###############################################################
#  Generated by:      Cadence Innovus 25.11-s102_1
#  OS:                Linux x86_64(Host ID ece-rhelsrv)
#  Generated on:      Sun Oct 11 20:42:43 2026
#  Design:            chip_top
#  Command:           write_lef_abstract /nethome/sgupta943/physical-design-onboarding-F26/outputs/apr/DBS/chip_top.lef -specifyTopLayer 5 -stripePin -extractBlockPGPinLayers 5
###############################################################

VERSION 5.8 ;

BUSBITCHARS "[]" ;
DIVIDERCHAR "/" ;

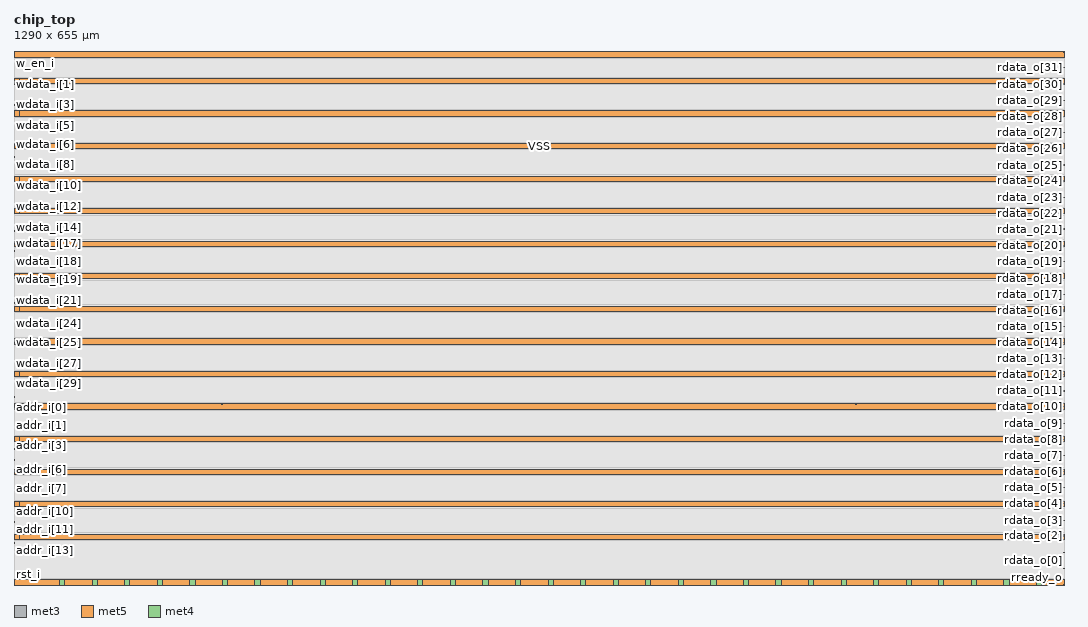
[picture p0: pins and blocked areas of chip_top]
MACRO chip_top
  CLASS BLOCK ;
  SIZE 1290.000000 BY 655.000000 ;
  FOREIGN chip_top 0.000000 0.000000 ;
  ORIGIN 0 0 ;
  SYMMETRY X Y R90 ;
  PIN clk_i
    DIRECTION INPUT ;
    USE SIGNAL ;
    PORT
      LAYER met3 ;
        RECT 0.000000 0.360000 0.800000 0.660000 ;
    END
  END clk_i
  PIN rst_i
    DIRECTION INPUT ;
    USE SIGNAL ;
    PORT
      LAYER met3 ;
        RECT 0.000000 12.560000 0.800000 12.860000 ;
    END
  END rst_i
  PIN en_cpu_i
    DIRECTION INPUT ;
    USE SIGNAL ;
    PORT
      LAYER met3 ;
        RECT 0.000000 25.980000 0.800000 26.280000 ;
    END
  END en_cpu_i
  PIN halt_cpu_i
    DIRECTION INPUT ;
    USE SIGNAL ;
    PORT
      LAYER met3 ;
        RECT 0.000000 39.400000 0.800000 39.700000 ;
    END
  END halt_cpu_i
  PIN cpu_halted_o
    DIRECTION OUTPUT ;
    USE SIGNAL ;
    PORT
      LAYER met3 ;
        RECT 1289.200000 654.280000 1290.000000 654.580000 ;
    END
  END cpu_halted_o
  PIN addr_i[13]
    DIRECTION INPUT ;
    USE SIGNAL ;
    PORT
      LAYER met3 ;
        RECT 0.000000 51.600000 0.800000 51.900000 ;
    END
  END addr_i[13]
  PIN addr_i[12]
    DIRECTION INPUT ;
    USE SIGNAL ;
    PORT
      LAYER met3 ;
        RECT 0.000000 64.410000 0.800000 64.710000 ;
    END
  END addr_i[12]
  PIN addr_i[11]
    DIRECTION INPUT ;
    USE SIGNAL ;
    PORT
      LAYER met3 ;
        RECT 0.000000 77.220000 0.800000 77.520000 ;
    END
  END addr_i[11]
  PIN addr_i[10]
    DIRECTION INPUT ;
    USE SIGNAL ;
    PORT
      LAYER met3 ;
        RECT 0.000000 90.030000 0.800000 90.330000 ;
    END
  END addr_i[10]
  PIN addr_i[9]
    DIRECTION INPUT ;
    USE SIGNAL ;
    PORT
      LAYER met3 ;
        RECT 0.000000 102.840000 0.800000 103.140000 ;
    END
  END addr_i[9]
  PIN addr_i[8]
    DIRECTION INPUT ;
    USE SIGNAL ;
    PORT
      LAYER met3 ;
        RECT 0.000000 115.650000 0.800000 115.950000 ;
    END
  END addr_i[8]
  PIN addr_i[7]
    DIRECTION INPUT ;
    USE SIGNAL ;
    PORT
      LAYER met3 ;
        RECT 0.000000 128.460000 0.800000 128.760000 ;
    END
  END addr_i[7]
  PIN addr_i[6]
    DIRECTION INPUT ;
    USE SIGNAL ;
    PORT
      LAYER met3 ;
        RECT 0.000000 141.270000 0.800000 141.570000 ;
    END
  END addr_i[6]
  PIN addr_i[5]
    DIRECTION INPUT ;
    USE SIGNAL ;
    PORT
      LAYER met3 ;
        RECT 0.000000 153.470000 0.800000 153.770000 ;
    END
  END addr_i[5]
  PIN addr_i[4]
    DIRECTION INPUT ;
    USE SIGNAL ;
    PORT
      LAYER met3 ;
        RECT 0.000000 166.890000 0.800000 167.190000 ;
    END
  END addr_i[4]
  PIN addr_i[3]
    DIRECTION INPUT ;
    USE SIGNAL ;
    PORT
      LAYER met3 ;
        RECT 0.000000 180.310000 0.800000 180.610000 ;
    END
  END addr_i[3]
  PIN addr_i[2]
    DIRECTION INPUT ;
    USE SIGNAL ;
    PORT
      LAYER met3 ;
        RECT 0.000000 192.510000 0.800000 192.810000 ;
    END
  END addr_i[2]
  PIN addr_i[1]
    DIRECTION INPUT ;
    USE SIGNAL ;
    PORT
      LAYER met3 ;
        RECT 0.000000 205.320000 0.800000 205.620000 ;
    END
  END addr_i[1]
  PIN addr_i[0]
    DIRECTION INPUT ;
    USE SIGNAL ;
    PORT
      LAYER met3 ;
        RECT 0.000000 218.130000 0.800000 218.430000 ;
    END
  END addr_i[0]
  PIN wdata_i[31]
    DIRECTION INPUT ;
    USE SIGNAL ;
    PORT
      LAYER met3 ;
        RECT 0.000000 230.940000 0.800000 231.240000 ;
    END
  END wdata_i[31]
  PIN wdata_i[30]
    DIRECTION INPUT ;
    USE SIGNAL ;
    PORT
      LAYER met3 ;
        RECT 0.000000 243.750000 0.800000 244.050000 ;
    END
  END wdata_i[30]
  PIN wdata_i[29]
    DIRECTION INPUT ;
    USE SIGNAL ;
    PORT
      LAYER met3 ;
        RECT 0.000000 256.560000 0.800000 256.860000 ;
    END
  END wdata_i[29]
  PIN wdata_i[28]
    DIRECTION INPUT ;
    USE SIGNAL ;
    PORT
      LAYER met3 ;
        RECT 0.000000 269.370000 0.800000 269.670000 ;
    END
  END wdata_i[28]
  PIN wdata_i[27]
    DIRECTION INPUT ;
    USE SIGNAL ;
    PORT
      LAYER met3 ;
        RECT 0.000000 282.180000 0.800000 282.480000 ;
    END
  END wdata_i[27]
  PIN wdata_i[26]
    DIRECTION INPUT ;
    USE SIGNAL ;
    PORT
      LAYER met3 ;
        RECT 0.000000 294.380000 0.800000 294.680000 ;
    END
  END wdata_i[26]
  PIN wdata_i[25]
    DIRECTION INPUT ;
    USE SIGNAL ;
    PORT
      LAYER met3 ;
        RECT 0.000000 307.800000 0.800000 308.100000 ;
    END
  END wdata_i[25]
  PIN wdata_i[24]
    DIRECTION INPUT ;
    USE SIGNAL ;
    PORT
      LAYER met3 ;
        RECT 0.000000 321.220000 0.800000 321.520000 ;
    END
  END wdata_i[24]
  PIN wdata_i[23]
    DIRECTION INPUT ;
    USE SIGNAL ;
    PORT
      LAYER met3 ;
        RECT 0.000000 333.420000 0.800000 333.720000 ;
    END
  END wdata_i[23]
  PIN wdata_i[22]
    DIRECTION INPUT ;
    USE SIGNAL ;
    PORT
      LAYER met3 ;
        RECT 0.000000 346.230000 0.800000 346.530000 ;
    END
  END wdata_i[22]
  PIN wdata_i[21]
    DIRECTION INPUT ;
    USE SIGNAL ;
    PORT
      LAYER met3 ;
        RECT 0.000000 359.040000 0.800000 359.340000 ;
    END
  END wdata_i[21]
  PIN wdata_i[20]
    DIRECTION INPUT ;
    USE SIGNAL ;
    PORT
      LAYER met3 ;
        RECT 0.000000 371.850000 0.800000 372.150000 ;
    END
  END wdata_i[20]
  PIN wdata_i[19]
    DIRECTION INPUT ;
    USE SIGNAL ;
    PORT
      LAYER met3 ;
        RECT 0.000000 384.660000 0.800000 384.960000 ;
    END
  END wdata_i[19]
  PIN wdata_i[18]
    DIRECTION INPUT ;
    USE SIGNAL ;
    PORT
      LAYER met3 ;
        RECT 0.000000 397.470000 0.800000 397.770000 ;
    END
  END wdata_i[18]
  PIN wdata_i[17]
    DIRECTION INPUT ;
    USE SIGNAL ;
    PORT
      LAYER met3 ;
        RECT 0.000000 410.280000 0.800000 410.580000 ;
    END
  END wdata_i[17]
  PIN wdata_i[16]
    DIRECTION INPUT ;
    USE SIGNAL ;
    PORT
      LAYER met3 ;
        RECT 0.000000 423.090000 0.800000 423.390000 ;
    END
  END wdata_i[16]
  PIN wdata_i[15]
    DIRECTION INPUT ;
    USE SIGNAL ;
    PORT
      LAYER met3 ;
        RECT 0.000000 434.680000 0.800000 434.980000 ;
    END
  END wdata_i[15]
  PIN wdata_i[14]
    DIRECTION INPUT ;
    USE SIGNAL ;
    PORT
      LAYER met3 ;
        RECT 0.000000 448.710000 0.800000 449.010000 ;
    END
  END wdata_i[14]
  PIN wdata_i[13]
    DIRECTION INPUT ;
    USE SIGNAL ;
    PORT
      LAYER met3 ;
        RECT 0.000000 461.520000 0.800000 461.820000 ;
    END
  END wdata_i[13]
  PIN wdata_i[12]
    DIRECTION INPUT ;
    USE SIGNAL ;
    PORT
      LAYER met3 ;
        RECT 0.000000 474.330000 0.800000 474.630000 ;
    END
  END wdata_i[12]
  PIN wdata_i[11]
    DIRECTION INPUT ;
    USE SIGNAL ;
    PORT
      LAYER met3 ;
        RECT 0.000000 487.140000 0.800000 487.440000 ;
    END
  END wdata_i[11]
  PIN wdata_i[10]
    DIRECTION INPUT ;
    USE SIGNAL ;
    PORT
      LAYER met3 ;
        RECT 0.000000 499.950000 0.800000 500.250000 ;
    END
  END wdata_i[10]
  PIN wdata_i[9]
    DIRECTION INPUT ;
    USE SIGNAL ;
    PORT
      LAYER met3 ;
        RECT 0.000000 512.760000 0.800000 513.060000 ;
    END
  END wdata_i[9]
  PIN wdata_i[8]
    DIRECTION INPUT ;
    USE SIGNAL ;
    PORT
      LAYER met3 ;
        RECT 0.000000 525.570000 0.800000 525.870000 ;
    END
  END wdata_i[8]
  PIN wdata_i[7]
    DIRECTION INPUT ;
    USE SIGNAL ;
    PORT
      LAYER met3 ;
        RECT 0.000000 538.380000 0.800000 538.680000 ;
    END
  END wdata_i[7]
  PIN wdata_i[6]
    DIRECTION INPUT ;
    USE SIGNAL ;
    PORT
      LAYER met3 ;
        RECT 0.000000 551.190000 0.800000 551.490000 ;
    END
  END wdata_i[6]
  PIN wdata_i[5]
    DIRECTION INPUT ;
    USE SIGNAL ;
    PORT
      LAYER met3 ;
        RECT 0.000000 564.000000 0.800000 564.300000 ;
    END
  END wdata_i[5]
  PIN wdata_i[4]
    DIRECTION INPUT ;
    USE SIGNAL ;
    PORT
      LAYER met3 ;
        RECT 0.000000 577.420000 0.800000 577.720000 ;
    END
  END wdata_i[4]
  PIN wdata_i[3]
    DIRECTION INPUT ;
    USE SIGNAL ;
    PORT
      LAYER met3 ;
        RECT 0.000000 589.620000 0.800000 589.920000 ;
    END
  END wdata_i[3]
  PIN wdata_i[2]
    DIRECTION INPUT ;
    USE SIGNAL ;
    PORT
      LAYER met3 ;
        RECT 0.000000 602.430000 0.800000 602.730000 ;
    END
  END wdata_i[2]
  PIN wdata_i[1]
    DIRECTION INPUT ;
    USE SIGNAL ;
    PORT
      LAYER met3 ;
        RECT 0.000000 615.240000 0.800000 615.540000 ;
    END
  END wdata_i[1]
  PIN wdata_i[0]
    DIRECTION INPUT ;
    USE SIGNAL ;
    PORT
      LAYER met3 ;
        RECT 0.000000 628.050000 0.800000 628.350000 ;
    END
  END wdata_i[0]
  PIN w_en_i
    DIRECTION INPUT ;
    USE SIGNAL ;
    PORT
      LAYER met3 ;
        RECT 0.000000 640.860000 0.800000 641.160000 ;
    END
  END w_en_i
  PIN r_en_i
    DIRECTION INPUT ;
    USE SIGNAL ;
    PORT
      LAYER met3 ;
        RECT 0.000000 653.670000 0.800000 653.970000 ;
    END
  END r_en_i
  PIN rdata_o[31]
    DIRECTION OUTPUT ;
    USE SIGNAL ;
    PORT
      LAYER met3 ;
        RECT 1289.200000 635.370000 1290.000000 635.670000 ;
    END
  END rdata_o[31]
  PIN rdata_o[30]
    DIRECTION OUTPUT ;
    USE SIGNAL ;
    PORT
      LAYER met3 ;
        RECT 1289.200000 615.240000 1290.000000 615.540000 ;
    END
  END rdata_o[30]
  PIN rdata_o[29]
    DIRECTION OUTPUT ;
    USE SIGNAL ;
    PORT
      LAYER met3 ;
        RECT 1289.200000 595.110000 1290.000000 595.410000 ;
    END
  END rdata_o[29]
  PIN rdata_o[28]
    DIRECTION OUTPUT ;
    USE SIGNAL ;
    PORT
      LAYER met3 ;
        RECT 1289.200000 575.590000 1290.000000 575.890000 ;
    END
  END rdata_o[28]
  PIN rdata_o[27]
    DIRECTION OUTPUT ;
    USE SIGNAL ;
    PORT
      LAYER met3 ;
        RECT 1289.200000 555.460000 1290.000000 555.760000 ;
    END
  END rdata_o[27]
  PIN rdata_o[26]
    DIRECTION OUTPUT ;
    USE SIGNAL ;
    PORT
      LAYER met3 ;
        RECT 1289.200000 535.940000 1290.000000 536.240000 ;
    END
  END rdata_o[26]
  PIN rdata_o[25]
    DIRECTION OUTPUT ;
    USE SIGNAL ;
    PORT
      LAYER met3 ;
        RECT 1289.200000 515.810000 1290.000000 516.110000 ;
    END
  END rdata_o[25]
  PIN rdata_o[24]
    DIRECTION OUTPUT ;
    USE SIGNAL ;
    PORT
      LAYER met3 ;
        RECT 1289.200000 496.290000 1290.000000 496.590000 ;
    END
  END rdata_o[24]
  PIN rdata_o[23]
    DIRECTION OUTPUT ;
    USE SIGNAL ;
    PORT
      LAYER met3 ;
        RECT 1289.200000 476.160000 1290.000000 476.460000 ;
    END
  END rdata_o[23]
  PIN rdata_o[22]
    DIRECTION OUTPUT ;
    USE SIGNAL ;
    PORT
      LAYER met3 ;
        RECT 1289.200000 456.640000 1290.000000 456.940000 ;
    END
  END rdata_o[22]
  PIN rdata_o[21]
    DIRECTION OUTPUT ;
    USE SIGNAL ;
    PORT
      LAYER met3 ;
        RECT 1289.200000 437.120000 1290.000000 437.420000 ;
    END
  END rdata_o[21]
  PIN rdata_o[20]
    DIRECTION OUTPUT ;
    USE SIGNAL ;
    PORT
      LAYER met3 ;
        RECT 1289.200000 416.990000 1290.000000 417.290000 ;
    END
  END rdata_o[20]
  PIN rdata_o[19]
    DIRECTION OUTPUT ;
    USE SIGNAL ;
    PORT
      LAYER met3 ;
        RECT 1289.200000 396.860000 1290.000000 397.160000 ;
    END
  END rdata_o[19]
  PIN rdata_o[18]
    DIRECTION OUTPUT ;
    USE SIGNAL ;
    PORT
      LAYER met3 ;
        RECT 1289.200000 376.730000 1290.000000 377.030000 ;
    END
  END rdata_o[18]
  PIN rdata_o[17]
    DIRECTION OUTPUT ;
    USE SIGNAL ;
    PORT
      LAYER met3 ;
        RECT 1289.200000 357.210000 1290.000000 357.510000 ;
    END
  END rdata_o[17]
  PIN rdata_o[16]
    DIRECTION OUTPUT ;
    USE SIGNAL ;
    PORT
      LAYER met3 ;
        RECT 1289.200000 337.690000 1290.000000 337.990000 ;
    END
  END rdata_o[16]
  PIN rdata_o[15]
    DIRECTION OUTPUT ;
    USE SIGNAL ;
    PORT
      LAYER met3 ;
        RECT 1289.200000 317.560000 1290.000000 317.860000 ;
    END
  END rdata_o[15]
  PIN rdata_o[14]
    DIRECTION OUTPUT ;
    USE SIGNAL ;
    PORT
      LAYER met3 ;
        RECT 1289.200000 298.040000 1290.000000 298.340000 ;
    END
  END rdata_o[14]
  PIN rdata_o[13]
    DIRECTION OUTPUT ;
    USE SIGNAL ;
    PORT
      LAYER met3 ;
        RECT 1289.200000 277.910000 1290.000000 278.210000 ;
    END
  END rdata_o[13]
  PIN rdata_o[12]
    DIRECTION OUTPUT ;
    USE SIGNAL ;
    PORT
      LAYER met3 ;
        RECT 1289.200000 258.390000 1290.000000 258.690000 ;
    END
  END rdata_o[12]
  PIN rdata_o[11]
    DIRECTION OUTPUT ;
    USE SIGNAL ;
    PORT
      LAYER met3 ;
        RECT 1289.200000 238.260000 1290.000000 238.560000 ;
    END
  END rdata_o[11]
  PIN rdata_o[10]
    DIRECTION OUTPUT ;
    USE SIGNAL ;
    PORT
      LAYER met3 ;
        RECT 1289.200000 218.740000 1290.000000 219.040000 ;
    END
  END rdata_o[10]
  PIN rdata_o[9]
    DIRECTION OUTPUT ;
    USE SIGNAL ;
    PORT
      LAYER met3 ;
        RECT 1289.200000 198.610000 1290.000000 198.910000 ;
    END
  END rdata_o[9]
  PIN rdata_o[8]
    DIRECTION OUTPUT ;
    USE SIGNAL ;
    PORT
      LAYER met3 ;
        RECT 1289.200000 178.480000 1290.000000 178.780000 ;
    END
  END rdata_o[8]
  PIN rdata_o[7]
    DIRECTION OUTPUT ;
    USE SIGNAL ;
    PORT
      LAYER met3 ;
        RECT 1289.200000 158.960000 1290.000000 159.260000 ;
    END
  END rdata_o[7]
  PIN rdata_o[6]
    DIRECTION OUTPUT ;
    USE SIGNAL ;
    PORT
      LAYER met3 ;
        RECT 1289.200000 139.440000 1290.000000 139.740000 ;
    END
  END rdata_o[6]
  PIN rdata_o[5]
    DIRECTION OUTPUT ;
    USE SIGNAL ;
    PORT
      LAYER met3 ;
        RECT 1289.200000 119.310000 1290.000000 119.610000 ;
    END
  END rdata_o[5]
  PIN rdata_o[4]
    DIRECTION OUTPUT ;
    USE SIGNAL ;
    PORT
      LAYER met3 ;
        RECT 1289.200000 99.790000 1290.000000 100.090000 ;
    END
  END rdata_o[4]
  PIN rdata_o[3]
    DIRECTION OUTPUT ;
    USE SIGNAL ;
    PORT
      LAYER met3 ;
        RECT 1289.200000 79.050000 1290.000000 79.350000 ;
    END
  END rdata_o[3]
  PIN rdata_o[2]
    DIRECTION OUTPUT ;
    USE SIGNAL ;
    PORT
      LAYER met3 ;
        RECT 1289.200000 60.140000 1290.000000 60.440000 ;
    END
  END rdata_o[2]
  PIN rdata_o[1]
    DIRECTION OUTPUT ;
    USE SIGNAL ;
    PORT
      LAYER met3 ;
        RECT 1289.200000 40.010000 1290.000000 40.310000 ;
    END
  END rdata_o[1]
  PIN rdata_o[0]
    DIRECTION OUTPUT ;
    USE SIGNAL ;
    PORT
      LAYER met3 ;
        RECT 1289.200000 20.490000 1290.000000 20.790000 ;
    END
  END rdata_o[0]
  PIN rready_o
    DIRECTION OUTPUT ;
    USE SIGNAL ;
    PORT
      LAYER met3 ;
        RECT 1289.200000 0.360000 1290.000000 0.660000 ;
    END
  END rready_o
  PIN VSS
    DIRECTION INOUT ;
    USE GROUND ;
    PORT
      LAYER met5 ;
        RECT 0.000000 56.060000 6.400000 62.460000 ;
    END
    PORT
      LAYER met5 ;
        RECT 0.000000 96.060000 6.400000 102.460000 ;
    END
    PORT
      LAYER met5 ;
        RECT 0.000000 136.060000 6.400000 142.460000 ;
    END
    PORT
      LAYER met5 ;
        RECT 0.000000 176.060000 6.400000 182.460000 ;
    END
    PORT
      LAYER met5 ;
        RECT 0.000000 216.060000 6.400000 222.460000 ;
    END
    PORT
      LAYER met5 ;
        RECT 0.000000 256.060000 6.400000 262.460000 ;
    END
    PORT
      LAYER met5 ;
        RECT 0.000000 296.060000 6.400000 302.460000 ;
    END
    PORT
      LAYER met5 ;
        RECT 0.000000 336.060000 6.400000 342.460000 ;
    END
    PORT
      LAYER met5 ;
        RECT 0.000000 376.060000 6.400000 382.460000 ;
    END
    PORT
      LAYER met5 ;
        RECT 0.000000 416.060000 6.400000 422.460000 ;
    END
    PORT
      LAYER met5 ;
        RECT 0.000000 456.060000 6.400000 462.460000 ;
    END
    PORT
      LAYER met5 ;
        RECT 0.000000 496.060000 6.400000 502.460000 ;
    END
    PORT
      LAYER met5 ;
        RECT 0.000000 536.060000 6.400000 542.460000 ;
    END
    PORT
      LAYER met5 ;
        RECT 0.000000 576.060000 6.400000 582.460000 ;
    END
    PORT
      LAYER met5 ;
        RECT 0.000000 616.060000 6.400000 622.460000 ;
    END
    PORT
      LAYER met4 ;
        RECT 56.060000 0.000000 62.460000 6.400000 ;
    END
    PORT
      LAYER met4 ;
        RECT 96.060000 0.000000 102.460000 6.400000 ;
    END
    PORT
      LAYER met4 ;
        RECT 136.060000 0.000000 142.460000 6.400000 ;
    END
    PORT
      LAYER met4 ;
        RECT 176.060000 0.000000 182.460000 6.400000 ;
    END
    PORT
      LAYER met4 ;
        RECT 216.060000 0.000000 222.460000 6.400000 ;
    END
    PORT
      LAYER met4 ;
        RECT 256.060000 0.000000 262.460000 6.400000 ;
    END
    PORT
      LAYER met4 ;
        RECT 296.060000 0.000000 302.460000 6.400000 ;
    END
    PORT
      LAYER met4 ;
        RECT 336.060000 0.000000 342.460000 6.400000 ;
    END
    PORT
      LAYER met4 ;
        RECT 376.060000 0.000000 382.460000 6.400000 ;
    END
    PORT
      LAYER met4 ;
        RECT 416.060000 0.000000 422.460000 6.400000 ;
    END
    PORT
      LAYER met4 ;
        RECT 456.060000 0.000000 462.460000 6.400000 ;
    END
    PORT
      LAYER met4 ;
        RECT 496.060000 0.000000 502.460000 6.400000 ;
    END
    PORT
      LAYER met4 ;
        RECT 536.060000 0.000000 542.460000 6.400000 ;
    END
    PORT
      LAYER met4 ;
        RECT 576.060000 0.000000 582.460000 6.400000 ;
    END
    PORT
      LAYER met4 ;
        RECT 616.060000 0.000000 622.460000 6.400000 ;
    END
    PORT
      LAYER met4 ;
        RECT 656.060000 0.000000 662.460000 6.400000 ;
    END
    PORT
      LAYER met4 ;
        RECT 696.060000 0.000000 702.460000 6.400000 ;
    END
    PORT
      LAYER met4 ;
        RECT 736.060000 0.000000 742.460000 6.400000 ;
    END
    PORT
      LAYER met4 ;
        RECT 776.060000 0.000000 782.460000 6.400000 ;
    END
    PORT
      LAYER met4 ;
        RECT 816.060000 0.000000 822.460000 6.400000 ;
    END
    PORT
      LAYER met4 ;
        RECT 856.060000 0.000000 862.460000 6.400000 ;
    END
    PORT
      LAYER met4 ;
        RECT 896.060000 0.000000 902.460000 6.400000 ;
    END
    PORT
      LAYER met4 ;
        RECT 936.060000 0.000000 942.460000 6.400000 ;
    END
    PORT
      LAYER met4 ;
        RECT 976.060000 0.000000 982.460000 6.400000 ;
    END
    PORT
      LAYER met4 ;
        RECT 1016.060000 0.000000 1022.460000 6.400000 ;
    END
    PORT
      LAYER met4 ;
        RECT 1056.060000 0.000000 1062.460000 6.400000 ;
    END
    PORT
      LAYER met4 ;
        RECT 1096.060000 0.000000 1102.460000 6.400000 ;
    END
    PORT
      LAYER met4 ;
        RECT 1136.060000 0.000000 1142.460000 6.400000 ;
    END
    PORT
      LAYER met4 ;
        RECT 1176.060000 0.000000 1182.460000 6.400000 ;
    END
    PORT
      LAYER met4 ;
        RECT 1216.060000 0.000000 1222.460000 6.400000 ;
    END
    PORT
      LAYER met4 ;
        RECT 1256.060000 0.000000 1262.460000 6.400000 ;
    END

# P/G power stripe data as pin
    PORT
      LAYER met5 ;
        RECT 0.000000 0.000000 1290.000000 6.400000 ;
        RECT 0.000000 56.060000 1290.000000 62.460000 ;
        RECT 0.000000 136.060000 1290.000000 142.460000 ;
        RECT 0.000000 96.060000 1290.000000 102.460000 ;
        RECT 0.000000 296.060000 1290.000000 302.460000 ;
        RECT 0.000000 256.060000 1290.000000 262.460000 ;
        RECT 0.000000 216.060000 1290.000000 222.460000 ;
        RECT 0.000000 176.060000 1290.000000 182.460000 ;
        RECT 0.000000 648.600000 1290.000000 655.000000 ;
        RECT 0.000000 456.060000 1290.000000 462.460000 ;
        RECT 0.000000 416.060000 1290.000000 422.460000 ;
        RECT 0.000000 376.060000 1290.000000 382.460000 ;
        RECT 0.000000 336.060000 1290.000000 342.460000 ;
        RECT 0.000000 536.060000 1290.000000 542.460000 ;
        RECT 0.000000 496.060000 1290.000000 502.460000 ;
        RECT 0.000000 616.060000 1290.000000 622.460000 ;
        RECT 0.000000 576.060000 1290.000000 582.460000 ;
        RECT 254.960000 221.420000 256.560000 223.020000 ;
        RECT 1033.280000 221.420000 1034.880000 223.020000 ;
    END
# end of P/G power stripe data as pin

  END VSS
  OBS
    LAYER met1 ;
      RECT 0.000000 0.000000 1290.000000 655.000000 ;
    LAYER met2 ;
      RECT 0.000000 0.000000 1290.000000 655.000000 ;
    LAYER met3 ;
      RECT 0.000000 654.880000 1290.000000 655.000000 ;
      RECT 0.000000 654.270000 1288.900000 654.880000 ;
      RECT 1.100000 653.980000 1288.900000 654.270000 ;
      RECT 1.100000 653.370000 1290.000000 653.980000 ;
      RECT 0.000000 641.460000 1290.000000 653.370000 ;
      RECT 1.100000 640.560000 1290.000000 641.460000 ;
      RECT 0.000000 635.970000 1290.000000 640.560000 ;
      RECT 0.000000 635.070000 1288.900000 635.970000 ;
      RECT 0.000000 628.650000 1290.000000 635.070000 ;
      RECT 1.100000 627.750000 1290.000000 628.650000 ;
      RECT 0.000000 615.840000 1290.000000 627.750000 ;
      RECT 1.100000 614.940000 1288.900000 615.840000 ;
      RECT 0.000000 603.030000 1290.000000 614.940000 ;
      RECT 1.100000 602.130000 1290.000000 603.030000 ;
      RECT 0.000000 595.710000 1290.000000 602.130000 ;
      RECT 0.000000 594.810000 1288.900000 595.710000 ;
      RECT 0.000000 590.220000 1290.000000 594.810000 ;
      RECT 1.100000 589.320000 1290.000000 590.220000 ;
      RECT 0.000000 578.020000 1290.000000 589.320000 ;
      RECT 1.100000 577.120000 1290.000000 578.020000 ;
      RECT 0.000000 576.190000 1290.000000 577.120000 ;
      RECT 0.000000 575.290000 1288.900000 576.190000 ;
      RECT 0.000000 564.600000 1290.000000 575.290000 ;
      RECT 1.100000 563.700000 1290.000000 564.600000 ;
      RECT 0.000000 556.060000 1290.000000 563.700000 ;
      RECT 0.000000 555.160000 1288.900000 556.060000 ;
      RECT 0.000000 551.790000 1290.000000 555.160000 ;
      RECT 1.100000 550.890000 1290.000000 551.790000 ;
      RECT 0.000000 538.980000 1290.000000 550.890000 ;
      RECT 1.100000 538.080000 1290.000000 538.980000 ;
      RECT 0.000000 536.540000 1290.000000 538.080000 ;
      RECT 0.000000 535.640000 1288.900000 536.540000 ;
      RECT 0.000000 526.170000 1290.000000 535.640000 ;
      RECT 1.100000 525.270000 1290.000000 526.170000 ;
      RECT 0.000000 516.410000 1290.000000 525.270000 ;
      RECT 0.000000 515.510000 1288.900000 516.410000 ;
      RECT 0.000000 513.360000 1290.000000 515.510000 ;
      RECT 1.100000 512.460000 1290.000000 513.360000 ;
      RECT 0.000000 500.550000 1290.000000 512.460000 ;
      RECT 1.100000 499.650000 1290.000000 500.550000 ;
      RECT 0.000000 496.890000 1290.000000 499.650000 ;
      RECT 0.000000 495.990000 1288.900000 496.890000 ;
      RECT 0.000000 487.740000 1290.000000 495.990000 ;
      RECT 1.100000 486.840000 1290.000000 487.740000 ;
      RECT 0.000000 476.760000 1290.000000 486.840000 ;
      RECT 0.000000 475.860000 1288.900000 476.760000 ;
      RECT 0.000000 474.930000 1290.000000 475.860000 ;
      RECT 1.100000 474.030000 1290.000000 474.930000 ;
      RECT 0.000000 462.120000 1290.000000 474.030000 ;
      RECT 1.100000 461.220000 1290.000000 462.120000 ;
      RECT 0.000000 457.240000 1290.000000 461.220000 ;
      RECT 0.000000 456.340000 1288.900000 457.240000 ;
      RECT 0.000000 449.310000 1290.000000 456.340000 ;
      RECT 1.100000 448.410000 1290.000000 449.310000 ;
      RECT 0.000000 437.720000 1290.000000 448.410000 ;
      RECT 0.000000 436.820000 1288.900000 437.720000 ;
      RECT 0.000000 435.280000 1290.000000 436.820000 ;
      RECT 1.100000 434.380000 1290.000000 435.280000 ;
      RECT 0.000000 423.690000 1290.000000 434.380000 ;
      RECT 1.100000 422.790000 1290.000000 423.690000 ;
      RECT 0.000000 417.590000 1290.000000 422.790000 ;
      RECT 0.000000 416.690000 1288.900000 417.590000 ;
      RECT 0.000000 410.880000 1290.000000 416.690000 ;
      RECT 1.100000 409.980000 1290.000000 410.880000 ;
      RECT 0.000000 398.070000 1290.000000 409.980000 ;
      RECT 1.100000 397.460000 1290.000000 398.070000 ;
      RECT 1.100000 397.170000 1288.900000 397.460000 ;
      RECT 0.000000 396.560000 1288.900000 397.170000 ;
      RECT 0.000000 385.260000 1290.000000 396.560000 ;
      RECT 1.100000 384.360000 1290.000000 385.260000 ;
      RECT 0.000000 377.330000 1290.000000 384.360000 ;
      RECT 0.000000 376.430000 1288.900000 377.330000 ;
      RECT 0.000000 372.450000 1290.000000 376.430000 ;
      RECT 1.100000 371.550000 1290.000000 372.450000 ;
      RECT 0.000000 359.640000 1290.000000 371.550000 ;
      RECT 1.100000 358.740000 1290.000000 359.640000 ;
      RECT 0.000000 357.810000 1290.000000 358.740000 ;
      RECT 0.000000 356.910000 1288.900000 357.810000 ;
      RECT 0.000000 346.830000 1290.000000 356.910000 ;
      RECT 1.100000 345.930000 1290.000000 346.830000 ;
      RECT 0.000000 338.290000 1290.000000 345.930000 ;
      RECT 0.000000 337.390000 1288.900000 338.290000 ;
      RECT 0.000000 334.020000 1290.000000 337.390000 ;
      RECT 1.100000 333.120000 1290.000000 334.020000 ;
      RECT 0.000000 321.820000 1290.000000 333.120000 ;
      RECT 1.100000 320.920000 1290.000000 321.820000 ;
      RECT 0.000000 318.160000 1290.000000 320.920000 ;
      RECT 0.000000 317.260000 1288.900000 318.160000 ;
      RECT 0.000000 308.400000 1290.000000 317.260000 ;
      RECT 1.100000 307.500000 1290.000000 308.400000 ;
      RECT 0.000000 298.640000 1290.000000 307.500000 ;
      RECT 0.000000 297.740000 1288.900000 298.640000 ;
      RECT 0.000000 294.980000 1290.000000 297.740000 ;
      RECT 1.100000 294.080000 1290.000000 294.980000 ;
      RECT 0.000000 282.780000 1290.000000 294.080000 ;
      RECT 1.100000 281.880000 1290.000000 282.780000 ;
      RECT 0.000000 278.510000 1290.000000 281.880000 ;
      RECT 0.000000 277.610000 1288.900000 278.510000 ;
      RECT 0.000000 269.970000 1290.000000 277.610000 ;
      RECT 1.100000 269.070000 1290.000000 269.970000 ;
      RECT 0.000000 258.990000 1290.000000 269.070000 ;
      RECT 0.000000 258.090000 1288.900000 258.990000 ;
      RECT 0.000000 257.160000 1290.000000 258.090000 ;
      RECT 1.100000 256.260000 1290.000000 257.160000 ;
      RECT 0.000000 244.350000 1290.000000 256.260000 ;
      RECT 1.100000 243.450000 1290.000000 244.350000 ;
      RECT 0.000000 238.860000 1290.000000 243.450000 ;
      RECT 0.000000 237.960000 1288.900000 238.860000 ;
      RECT 0.000000 231.540000 1290.000000 237.960000 ;
      RECT 1.100000 230.640000 1290.000000 231.540000 ;
      RECT 0.000000 219.340000 1290.000000 230.640000 ;
      RECT 0.000000 218.730000 1288.900000 219.340000 ;
      RECT 1.100000 218.440000 1288.900000 218.730000 ;
      RECT 1.100000 217.830000 1290.000000 218.440000 ;
      RECT 0.000000 205.920000 1290.000000 217.830000 ;
      RECT 1.100000 205.020000 1290.000000 205.920000 ;
      RECT 0.000000 199.210000 1290.000000 205.020000 ;
      RECT 0.000000 198.310000 1288.900000 199.210000 ;
      RECT 0.000000 193.110000 1290.000000 198.310000 ;
      RECT 1.100000 192.210000 1290.000000 193.110000 ;
      RECT 0.000000 180.910000 1290.000000 192.210000 ;
      RECT 1.100000 180.010000 1290.000000 180.910000 ;
      RECT 0.000000 179.080000 1290.000000 180.010000 ;
      RECT 0.000000 178.180000 1288.900000 179.080000 ;
      RECT 0.000000 167.490000 1290.000000 178.180000 ;
      RECT 1.100000 166.590000 1290.000000 167.490000 ;
      RECT 0.000000 159.560000 1290.000000 166.590000 ;
      RECT 0.000000 158.660000 1288.900000 159.560000 ;
      RECT 0.000000 154.070000 1290.000000 158.660000 ;
      RECT 1.100000 153.170000 1290.000000 154.070000 ;
      RECT 0.000000 141.870000 1290.000000 153.170000 ;
      RECT 1.100000 140.970000 1290.000000 141.870000 ;
      RECT 0.000000 140.040000 1290.000000 140.970000 ;
      RECT 0.000000 139.140000 1288.900000 140.040000 ;
      RECT 0.000000 129.060000 1290.000000 139.140000 ;
      RECT 1.100000 128.160000 1290.000000 129.060000 ;
      RECT 0.000000 119.910000 1290.000000 128.160000 ;
      RECT 0.000000 119.010000 1288.900000 119.910000 ;
      RECT 0.000000 116.250000 1290.000000 119.010000 ;
      RECT 1.100000 115.350000 1290.000000 116.250000 ;
      RECT 0.000000 103.440000 1290.000000 115.350000 ;
      RECT 1.100000 102.540000 1290.000000 103.440000 ;
      RECT 0.000000 100.390000 1290.000000 102.540000 ;
      RECT 0.000000 99.490000 1288.900000 100.390000 ;
      RECT 0.000000 90.630000 1290.000000 99.490000 ;
      RECT 1.100000 89.730000 1290.000000 90.630000 ;
      RECT 0.000000 79.650000 1290.000000 89.730000 ;
      RECT 0.000000 78.750000 1288.900000 79.650000 ;
      RECT 0.000000 77.820000 1290.000000 78.750000 ;
      RECT 1.100000 76.920000 1290.000000 77.820000 ;
      RECT 0.000000 65.010000 1290.000000 76.920000 ;
      RECT 1.100000 64.110000 1290.000000 65.010000 ;
      RECT 0.000000 60.740000 1290.000000 64.110000 ;
      RECT 0.000000 59.840000 1288.900000 60.740000 ;
      RECT 0.000000 52.200000 1290.000000 59.840000 ;
      RECT 1.100000 51.300000 1290.000000 52.200000 ;
      RECT 0.000000 40.610000 1290.000000 51.300000 ;
      RECT 0.000000 40.000000 1288.900000 40.610000 ;
      RECT 1.100000 39.710000 1288.900000 40.000000 ;
      RECT 1.100000 39.100000 1290.000000 39.710000 ;
      RECT 0.000000 26.580000 1290.000000 39.100000 ;
      RECT 1.100000 25.680000 1290.000000 26.580000 ;
      RECT 0.000000 21.090000 1290.000000 25.680000 ;
      RECT 0.000000 20.190000 1288.900000 21.090000 ;
      RECT 0.000000 13.160000 1290.000000 20.190000 ;
      RECT 1.100000 12.260000 1290.000000 13.160000 ;
      RECT 0.000000 0.960000 1290.000000 12.260000 ;
      RECT 1.100000 0.060000 1288.900000 0.960000 ;
      RECT 0.000000 0.000000 1290.000000 0.060000 ;
    LAYER met4 ;
      RECT 0.000000 6.800000 1290.000000 655.000000 ;
      RECT 1262.860000 0.000000 1290.000000 6.800000 ;
      RECT 1222.860000 0.000000 1255.660000 6.800000 ;
      RECT 1182.860000 0.000000 1215.660000 6.800000 ;
      RECT 1142.860000 0.000000 1175.660000 6.800000 ;
      RECT 1102.860000 0.000000 1135.660000 6.800000 ;
      RECT 1062.860000 0.000000 1095.660000 6.800000 ;
      RECT 1022.860000 0.000000 1055.660000 6.800000 ;
      RECT 982.860000 0.000000 1015.660000 6.800000 ;
      RECT 942.860000 0.000000 975.660000 6.800000 ;
      RECT 902.860000 0.000000 935.660000 6.800000 ;
      RECT 862.860000 0.000000 895.660000 6.800000 ;
      RECT 822.860000 0.000000 855.660000 6.800000 ;
      RECT 782.860000 0.000000 815.660000 6.800000 ;
      RECT 742.860000 0.000000 775.660000 6.800000 ;
      RECT 702.860000 0.000000 735.660000 6.800000 ;
      RECT 662.860000 0.000000 695.660000 6.800000 ;
      RECT 622.860000 0.000000 655.660000 6.800000 ;
      RECT 582.860000 0.000000 615.660000 6.800000 ;
      RECT 542.860000 0.000000 575.660000 6.800000 ;
      RECT 502.860000 0.000000 535.660000 6.800000 ;
      RECT 462.860000 0.000000 495.660000 6.800000 ;
      RECT 422.860000 0.000000 455.660000 6.800000 ;
      RECT 382.860000 0.000000 415.660000 6.800000 ;
      RECT 342.860000 0.000000 375.660000 6.800000 ;
      RECT 302.860000 0.000000 335.660000 6.800000 ;
      RECT 262.860000 0.000000 295.660000 6.800000 ;
      RECT 222.860000 0.000000 255.660000 6.800000 ;
      RECT 182.860000 0.000000 215.660000 6.800000 ;
      RECT 142.860000 0.000000 175.660000 6.800000 ;
      RECT 102.860000 0.000000 135.660000 6.800000 ;
      RECT 62.860000 0.000000 95.660000 6.800000 ;
      RECT 0.000000 0.000000 55.660000 6.800000 ;
    LAYER met5 ;
      RECT 0.000000 624.060000 1290.000000 647.000000 ;
      RECT 0.000000 584.060000 1290.000000 614.460000 ;
      RECT 0.000000 544.060000 1290.000000 574.460000 ;
      RECT 0.000000 504.060000 1290.000000 534.460000 ;
      RECT 0.000000 464.060000 1290.000000 494.460000 ;
      RECT 0.000000 424.060000 1290.000000 454.460000 ;
      RECT 0.000000 384.060000 1290.000000 414.460000 ;
      RECT 0.000000 344.060000 1290.000000 374.460000 ;
      RECT 0.000000 304.060000 1290.000000 334.460000 ;
      RECT 0.000000 264.060000 1290.000000 294.460000 ;
      RECT 0.000000 224.620000 1290.000000 254.460000 ;
      RECT 1036.480000 224.060000 1290.000000 224.620000 ;
      RECT 258.160000 224.060000 1031.680000 224.620000 ;
      RECT 0.000000 224.060000 253.360000 224.620000 ;
      RECT 0.000000 184.060000 1290.000000 214.460000 ;
      RECT 0.000000 144.060000 1290.000000 174.460000 ;
      RECT 0.000000 104.060000 1290.000000 134.460000 ;
      RECT 0.000000 64.060000 1290.000000 94.460000 ;
      RECT 0.000000 8.000000 1290.000000 54.460000 ;
  END
END chip_top

END LIBRARY
